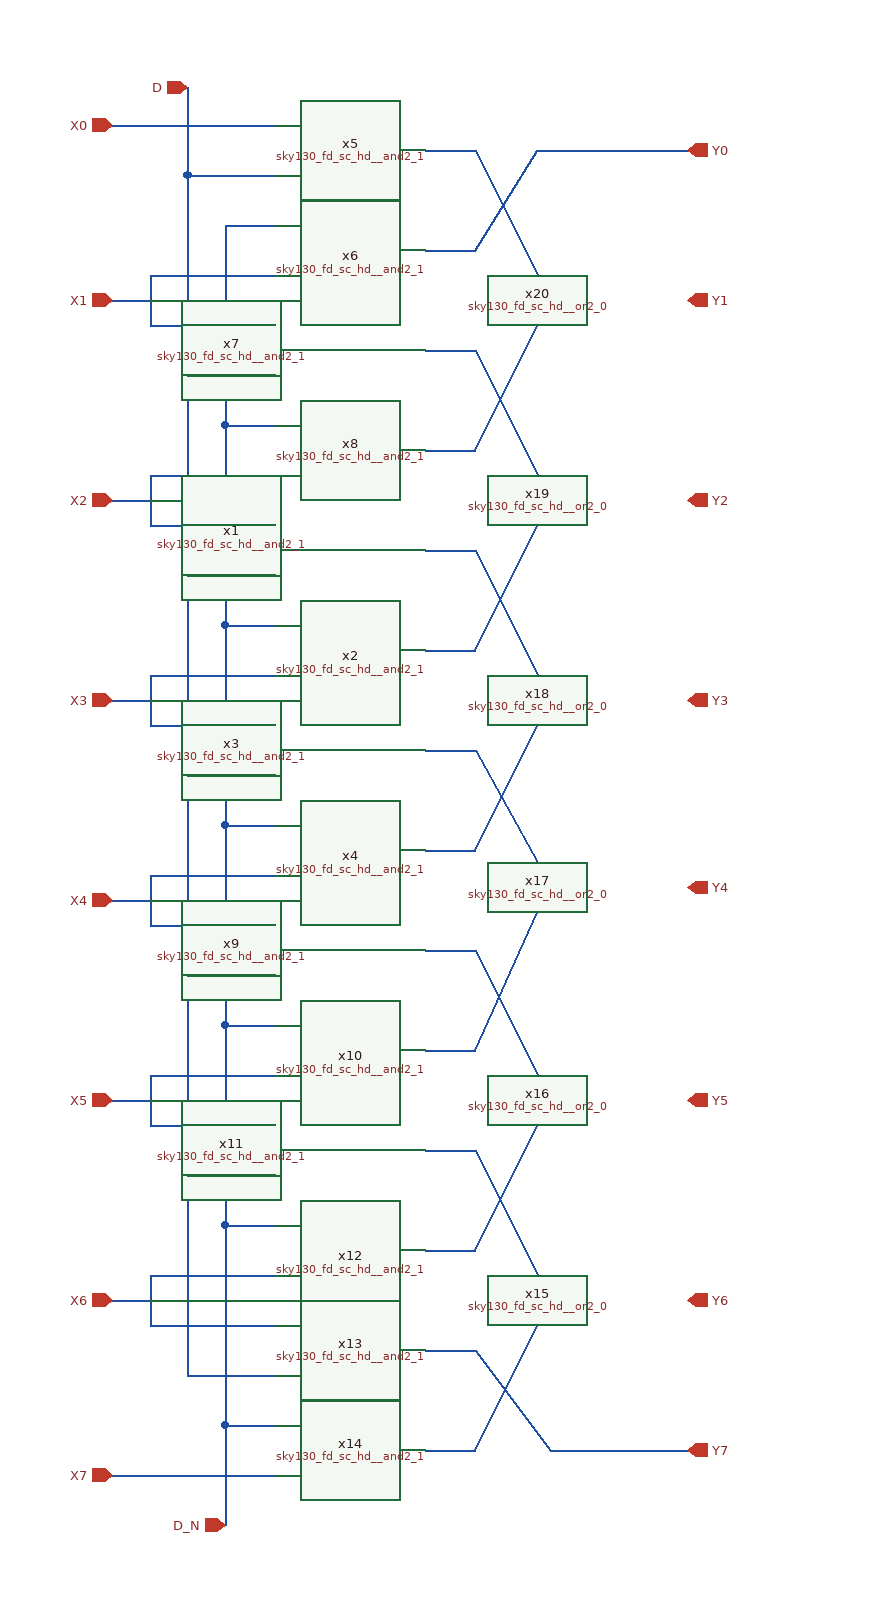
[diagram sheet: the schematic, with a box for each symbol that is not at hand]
v {xschem version=3.1.0 file_version=1.2
}
G {}
K {}
V {}
S {}
E {}
N 340 -1120 380 -1120 {
lab=#net1}
N 380 -1120 430 -1020 {
lab=#net1}
N 340 -880 380 -880 {
lab=#net2}
N 380 -880 430 -980 {
lab=#net2}
N 340 -1040 380 -1040 {
lab=Y0}
N 340 -960 380 -960 {
lab=#net3}
N 340 -800 380 -800 {
lab=#net4}
N 340 -720 380 -720 {
lab=#net5}
N 340 -640 380 -640 {
lab=#net6}
N 340 -480 380 -480 {
lab=#net7}
N 340 -400 380 -400 {
lab=#net8}
N 340 -560 380 -560 {
lab=#net9}
N 340 -320 380 -320 {
lab=#net10}
N 340 -240 380 -240 {
lab=#net11}
N 340 -160 380 -160 {
lab=Y7}
N 340 -80 380 -80 {
lab=#net12}
N 380 -1040 430 -1120 {
lab=Y0}
N 430 -1120 550 -1120 {
lab=Y0}
N 380 -160 440 -80 {
lab=Y7}
N 380 -960 430 -860 {
lab=#net3}
N 380 -720 430 -820 {
lab=#net5}
N 380 -800 430 -700 {
lab=#net4}
N 380 -560 430 -660 {
lab=#net9}
N 380 -640 430 -550 {
lab=#net6}
N 380 -400 430 -510 {
lab=#net8}
N 380 -480 430 -380 {
lab=#net7}
N 380 -240 430 -340 {
lab=#net11}
N 380 -320 430 -220 {
lab=#net10}
N 380 -80 430 -180 {
lab=#net12}
N 120 -860 220 -860 {
lab=X2}
N 120 -860 120 -820 {
lab=X2}
N 120 -820 220 -820 {
lab=X2}
N 90 -840 120 -840 {
lab=X2}
N 120 -1020 220 -1020 {
lab=X1}
N 120 -1020 120 -980 {
lab=X1}
N 120 -980 220 -980 {
lab=X1}
N 90 -1000 120 -1000 {
lab=X1}
N 120 -700 220 -700 {
lab=X3}
N 120 -700 120 -660 {
lab=X3}
N 120 -660 220 -660 {
lab=X3}
N 90 -680 120 -680 {
lab=X3}
N 120 -540 220 -540 {
lab=X4}
N 120 -540 120 -500 {
lab=X4}
N 120 -500 220 -500 {
lab=X4}
N 90 -520 120 -520 {
lab=X4}
N 120 -380 220 -380 {
lab=X5}
N 120 -380 120 -340 {
lab=X5}
N 120 -340 220 -340 {
lab=X5}
N 90 -360 120 -360 {
lab=X5}
N 120 -220 220 -220 {
lab=X6}
N 120 -220 120 -180 {
lab=X6}
N 120 -180 220 -180 {
lab=X6}
N 90 -200 120 -200 {
lab=X6}
N 90 -60 220 -60 {
lab=X7}
N 100 -1140 220 -1140 {
lab=X0}
N 150 -1100 220 -1100 {
lab=D}
N 150 -1170 150 -1100 {
lab=D}
N 150 -940 220 -940 {
lab=D}
N 150 -780 220 -780 {
lab=D}
N 150 -620 220 -620 {
lab=D}
N 150 -460 220 -460 {
lab=D}
N 160 -300 220 -300 {
lab=D}
N 150 -300 160 -300 {
lab=D}
N 150 -140 220 -140 {
lab=D}
N 150 -1100 150 -140 {
lab=D}
N 180 -100 180 -20 {
lab=GND}
N 180 -100 220 -100 {
lab=GND}
N 180 -260 180 -100 {
lab=GND}
N 180 -260 220 -260 {
lab=GND}
N 180 -420 180 -260 {
lab=GND}
N 180 -420 220 -420 {
lab=GND}
N 180 -580 180 -420 {
lab=GND}
N 180 -580 220 -580 {
lab=GND}
N 180 -740 180 -580 {
lab=GND}
N 180 -740 220 -740 {
lab=GND}
N 180 -900 180 -740 {
lab=GND}
N 180 -900 220 -900 {
lab=GND}
N 180 -1060 180 -900 {
lab=GND}
N 180 -1060 220 -1060 {
lab=GND}
N 90 -1140 100 -1140 {
lab=X0}
N 440 -80 550 -80 {
lab=Y7}
C {sky130_stdcells/sky130_fd_sc_hd__and2_1.sym} 280 -800 0 0 {name=x1 VGND=VGND VNB=VNB VPB=VPB VPWR=VPWR prefix=sky130_fd_sc_hd__ }
C {sky130_stdcells/sky130_fd_sc_hd__and2_1.sym} 280 -720 0 0 {name=x2 VGND=VGND VNB=VNB VPB=VPB VPWR=VPWR prefix=sky130_fd_sc_hd__ }
C {sky130_stdcells/sky130_fd_sc_hd__and2_1.sym} 280 -640 0 0 {name=x3 VGND=VGND VNB=VNB VPB=VPB VPWR=VPWR prefix=sky130_fd_sc_hd__ }
C {sky130_stdcells/sky130_fd_sc_hd__and2_1.sym} 280 -560 0 0 {name=x4 VGND=VGND VNB=VNB VPB=VPB VPWR=VPWR prefix=sky130_fd_sc_hd__ }
C {sky130_stdcells/sky130_fd_sc_hd__and2_1.sym} 280 -1120 0 0 {name=x5 VGND=VGND VNB=VNB VPB=VPB VPWR=VPWR prefix=sky130_fd_sc_hd__ }
C {sky130_stdcells/sky130_fd_sc_hd__and2_1.sym} 280 -1040 0 0 {name=x6 VGND=VGND VNB=VNB VPB=VPB VPWR=VPWR prefix=sky130_fd_sc_hd__ }
C {sky130_stdcells/sky130_fd_sc_hd__and2_1.sym} 280 -960 0 0 {name=x7 VGND=VGND VNB=VNB VPB=VPB VPWR=VPWR prefix=sky130_fd_sc_hd__ }
C {sky130_stdcells/sky130_fd_sc_hd__and2_1.sym} 280 -880 0 0 {name=x8 VGND=VGND VNB=VNB VPB=VPB VPWR=VPWR prefix=sky130_fd_sc_hd__ }
C {sky130_stdcells/sky130_fd_sc_hd__and2_1.sym} 280 -480 0 0 {name=x9 VGND=VGND VNB=VNB VPB=VPB VPWR=VPWR prefix=sky130_fd_sc_hd__ }
C {sky130_stdcells/sky130_fd_sc_hd__and2_1.sym} 280 -400 0 0 {name=x10 VGND=VGND VNB=VNB VPB=VPB VPWR=VPWR prefix=sky130_fd_sc_hd__ }
C {sky130_stdcells/sky130_fd_sc_hd__and2_1.sym} 280 -320 0 0 {name=x11 VGND=VGND VNB=VNB VPB=VPB VPWR=VPWR prefix=sky130_fd_sc_hd__ }
C {sky130_stdcells/sky130_fd_sc_hd__and2_1.sym} 280 -240 0 0 {name=x12 VGND=VGND VNB=VNB VPB=VPB VPWR=VPWR prefix=sky130_fd_sc_hd__ }
C {sky130_stdcells/sky130_fd_sc_hd__and2_1.sym} 280 -160 0 0 {name=x13 VGND=VGND VNB=VNB VPB=VPB VPWR=VPWR prefix=sky130_fd_sc_hd__ }
C {sky130_stdcells/sky130_fd_sc_hd__and2_1.sym} 280 -80 0 0 {name=x14 VGND=VGND VNB=VNB VPB=VPB VPWR=VPWR prefix=sky130_fd_sc_hd__ }
C {sky130_stdcells/sky130_fd_sc_hd__or2_0.sym} 490 -200 0 0 {name=x15 VGND=VGND VNB=VNB VPB=VPB VPWR=VPWR prefix=sky130_fd_sc_hd__ }
C {sky130_stdcells/sky130_fd_sc_hd__or2_0.sym} 490 -360 0 0 {name=x16 VGND=VGND VNB=VNB VPB=VPB VPWR=VPWR prefix=sky130_fd_sc_hd__ }
C {sky130_stdcells/sky130_fd_sc_hd__or2_0.sym} 490 -530 0 0 {name=x17 VGND=VGND VNB=VNB VPB=VPB VPWR=VPWR prefix=sky130_fd_sc_hd__ }
C {sky130_stdcells/sky130_fd_sc_hd__or2_0.sym} 490 -680 0 0 {name=x18 VGND=VGND VNB=VNB VPB=VPB VPWR=VPWR prefix=sky130_fd_sc_hd__ }
C {sky130_stdcells/sky130_fd_sc_hd__or2_0.sym} 490 -840 0 0 {name=x19 VGND=VGND VNB=VNB VPB=VPB VPWR=VPWR prefix=sky130_fd_sc_hd__ }
C {sky130_stdcells/sky130_fd_sc_hd__or2_0.sym} 490 -1000 0 0 {name=x20 VGND=VGND VNB=VNB VPB=VPB VPWR=VPWR prefix=sky130_fd_sc_hd__ }
C {devices/ipin.sym} 90 -1140 0 0 {name=p1 lab=X0}
C {devices/ipin.sym} 90 -1000 0 0 {name=p2 lab=X1}
C {devices/ipin.sym} 90 -840 0 0 {name=p3 lab=X2}
C {devices/ipin.sym} 90 -680 0 0 {name=p4 lab=X3}
C {devices/ipin.sym} 90 -520 0 0 {name=p5 lab=X4}
C {devices/ipin.sym} 90 -360 0 0 {name=p6 lab=X5}
C {devices/ipin.sym} 90 -200 0 0 {name=p7 lab=X6}
C {devices/ipin.sym} 90 -60 0 0 {name=p8 lab=X7}
C {devices/opin.sym} 550 -1120 0 0 {name=p9 lab=Y0}
C {devices/opin.sym} 550 -1000 0 0 {name=p10 lab=Y1}
C {devices/opin.sym} 550 -840 0 0 {name=p11 lab=Y2}
C {devices/opin.sym} 550 -680 0 0 {name=p12 lab=Y3}
C {devices/opin.sym} 550 -530 0 0 {name=p13 lab=Y4}
C {devices/opin.sym} 550 -360 0 0 {name=p14 lab=Y5}
C {devices/opin.sym} 550 -200 0 0 {name=p15 lab=Y6}
C {devices/opin.sym} 550 -80 0 0 {name=p16 lab=Y7}
C {devices/ipin.sym} 150 -1170 1 0 {name=p17 lab=D}
C {devices/ipin.sym} 180 -20 0 0 {name=p18 lab=D_N}
C {devices/verilog_preprocessor.sym} 0 -1380 0 0 {
name=s2  string="`include \\"/home/mihailo/pdk/volare/sky130/versions/032b059033c4cf67f94c5b7f0a44d936b8ff5aae/sky130A/libs.ref/sky130_fd_sc_hd/verilog/primitives.v\\""
}
C {devices/verilog_preprocessor.sym} 0 -1320 0 0 {
name=s3  string="`include \\"/home/mihailo/pdk/volare/sky130/versions/032b059033c4cf67f94c5b7f0a44d936b8ff5aae/sky130A/libs.ref/sky130_fd_sc_hd/verilog/sky130_fd_sc_hd.v\\""
}
